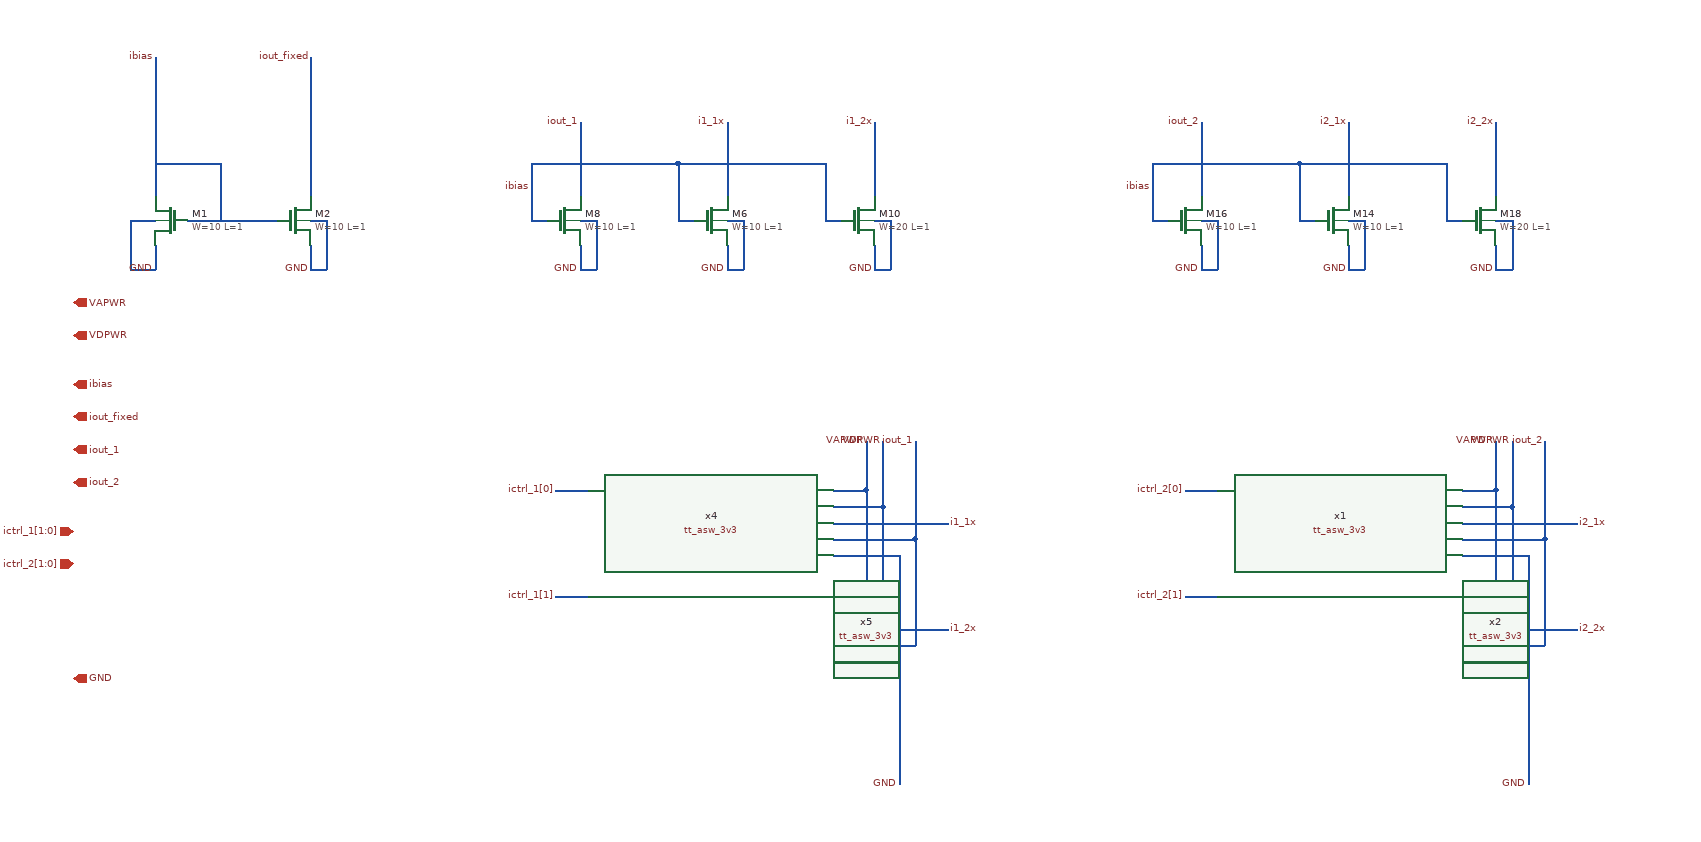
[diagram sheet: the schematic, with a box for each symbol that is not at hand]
v {xschem version=3.1.0 file_version=1.2
}
G {}
K {}
V {}
S {}
E {}
N 0 130 0 160 {
lab=GND}
N 80 30 80 100 {
lab=ibias}
N 190 130 190 160 {
lab=GND}
N 190 100 210 100 {
lab=GND}
N 210 100 210 160 {
lab=GND}
N -30 100 0 100 {
lab=GND}
N -30 100 -30 160 {
lab=GND}
N 190 -20 190 70 {
lab=iout_fixed}
N 0 30 80 30 {
lab=ibias}
N 0 -100 0 70 {
lab=ibias}
N 190 -100 190 -20 {
lab=iout_fixed}
N 830 600 970 600 {
lab=i1_2x}
N 460 30 460 100 {
lab=ibias}
N 700 -20 700 70 {
lab=i1_1x}
N 640 30 640 100 {
lab=ibias}
N 640 100 660 100 {
lab=ibias}
N 460 30 640 30 {
lab=ibias}
N 520 -20 520 70 {
lab=iout_1}
N 460 100 480 100 {
lab=ibias}
N 640 30 820 30 {
lab=ibias}
N 880 -20 880 70 {
lab=i1_2x}
N 820 30 820 100 {
lab=ibias}
N 820 100 840 100 {
lab=ibias}
N 490 430 530 430 {
lab=ictrl_1[0]}
N 490 560 530 560 {
lab=ictrl_1[1]}
N 830 430 870 430 {
lab=VAPWR}
N 830 560 870 560 {
lab=VAPWR}
N 830 450 890 450 {
lab=VDPWR}
N 830 580 890 580 {
lab=VDPWR}
N 830 510 910 510 {
lab=GND}
N 910 510 910 790 {
lab=GND}
N 830 640 910 640 {
lab=GND}
N 870 370 870 430 {
lab=VAPWR}
N 890 370 890 450 {
lab=VDPWR}
N 830 490 930 490 {
lab=iout_1}
N 830 620 930 620 {
lab=iout_1}
N 930 370 930 490 {
lab=iout_1}
N 830 470 970 470 {
lab=i1_1x}
N 830 600 970 600 {
lab=i1_2x}
N 1220 30 1220 100 {
lab=ibias}
N 1460 -20 1460 70 {
lab=i2_1x}
N 1400 30 1400 100 {
lab=ibias}
N 1400 100 1420 100 {
lab=ibias}
N 1220 30 1400 30 {
lab=ibias}
N 1280 -20 1280 70 {
lab=iout_2}
N 1220 100 1240 100 {
lab=ibias}
N 1400 30 1580 30 {
lab=ibias}
N 1640 -20 1640 70 {
lab=i2_2x}
N 1580 30 1580 100 {
lab=ibias}
N 1580 100 1600 100 {
lab=ibias}
N 1460 130 1460 160 {
lab=GND}
N 1480 100 1480 160 {
lab=GND}
N 1460 100 1480 100 {
lab=GND}
N 520 100 540 100 {
lab=GND}
N 540 100 540 160 {
lab=GND}
N 520 130 520 160 {
lab=GND}
N 700 100 720 100 {
lab=GND}
N 720 100 720 160 {
lab=GND}
N 700 130 700 160 {
lab=GND}
N 880 100 900 100 {
lab=GND}
N 900 100 900 160 {
lab=GND}
N 880 130 880 160 {
lab=GND}
N 1280 100 1300 100 {
lab=GND}
N 1300 100 1300 160 {
lab=GND}
N 1280 130 1280 160 {
lab=GND}
N 1640 100 1660 100 {
lab=GND}
N 1660 100 1660 160 {
lab=GND}
N 1640 130 1640 160 {
lab=GND}
N 1600 600 1740 600 {
lab=i2_2x}
N 1260 430 1300 430 {
lab=ictrl_2[0]}
N 1260 560 1300 560 {
lab=ictrl_2[1]}
N 1600 430 1640 430 {
lab=VAPWR}
N 1600 560 1640 560 {
lab=VAPWR}
N 1600 450 1660 450 {
lab=VDPWR}
N 1600 580 1660 580 {
lab=VDPWR}
N 1600 510 1680 510 {
lab=GND}
N 1680 510 1680 790 {
lab=GND}
N 1600 640 1680 640 {
lab=GND}
N 1640 370 1640 430 {
lab=VAPWR}
N 1660 370 1660 450 {
lab=VDPWR}
N 1600 490 1700 490 {
lab=iout_2}
N 1600 620 1700 620 {
lab=iout_2}
N 1700 370 1700 490 {
lab=iout_2}
N 1600 470 1740 470 {
lab=i2_1x}
N 1600 600 1740 600 {
lab=i2_2x}
N 40 100 150 100 {
lab=ibias}
N 1280 160 1300 160 {
lab=GND}
N 1460 160 1480 160 {
lab=GND}
N 1640 160 1660 160 {
lab=GND}
N 190 160 210 160 {
lab=GND}
N -30 160 -0 160 {
lab=GND}
N 520 160 540 160 {
lab=GND}
N 700 160 720 160 {
lab=GND}
N 880 160 900 160 {
lab=GND}
N 870 430 870 560 {
lab=VAPWR}
N 890 450 890 580 {
lab=VDPWR}
N 930 490 930 620 {
lab=iout_1}
N 1640 430 1640 560 {
lab=VAPWR}
N 1660 450 1660 580 {
lab=VDPWR}
N 1700 490 1700 620 {
lab=iout_2}
C {sky130_fd_pr/nfet_g5v0d10v5.sym} 20 100 0 1 {name=M1
L=1
W=10
nf=2
mult=1
ad="'int((nf+1)/2) * W/nf * 0.29'" 
pd="'2*int((nf+1)/2) * (W/nf + 0.29)'"
as="'int((nf+2)/2) * W/nf * 0.29'" 
ps="'2*int((nf+2)/2) * (W/nf + 0.29)'"
nrd="'0.29 / W'" nrs="'0.29 / W'"
sa=0 sb=0 sd=0
model=nfet_g5v0d10v5
spiceprefix=X
}
C {sky130_fd_pr/nfet_g5v0d10v5.sym} 170 100 0 0 {name=M2
L=1
W=10
nf=2
mult=1
ad="'int((nf+1)/2) * W/nf * 0.29'" 
pd="'2*int((nf+1)/2) * (W/nf + 0.29)'"
as="'int((nf+2)/2) * W/nf * 0.29'" 
ps="'2*int((nf+2)/2) * (W/nf + 0.29)'"
nrd="'0.29 / W'" nrs="'0.29 / W'"
sa=0 sb=0 sd=0
model=nfet_g5v0d10v5
spiceprefix=X
}
C {devices/iopin.sym} -100 300 0 1 {name=p8 lab=ibias}
C {devices/iopin.sym} -100 340 0 1 {name=p3 lab=iout_fixed}
C {devices/iopin.sym} -100 380 0 1 {name=p6 lab=iout_1}
C {devices/ipin.sym} -100 480 0 0 {name=p4 lab=ictrl_1[1:0]}
C {devices/ipin.sym} -100 520 0 0 {name=p5 lab=ictrl_2[1:0]}
C {devices/iopin.sym} -100 420 0 1 {name=p7 lab=iout_2}
C {devices/iopin.sym} -100 200 0 1 {name=p9 lab=VAPWR}
C {devices/iopin.sym} -100 240 0 1 {name=p10 lab=VDPWR}
C {sky130_fd_pr/nfet_g5v0d10v5.sym} 680 100 0 0 {name=M6
L=1
W=10
nf=2
mult=1
ad="'int((nf+1)/2) * W/nf * 0.29'" 
pd="'2*int((nf+1)/2) * (W/nf + 0.29)'"
as="'int((nf+2)/2) * W/nf * 0.29'" 
ps="'2*int((nf+2)/2) * (W/nf + 0.29)'"
nrd="'0.29 / W'" nrs="'0.29 / W'"
sa=0 sb=0 sd=0
model=nfet_g5v0d10v5
spiceprefix=X
}
C {sky130_fd_pr/nfet_g5v0d10v5.sym} 500 100 0 0 {name=M8
L=1
W=10
nf=2
mult=1
ad="'int((nf+1)/2) * W/nf * 0.29'" 
pd="'2*int((nf+1)/2) * (W/nf + 0.29)'"
as="'int((nf+2)/2) * W/nf * 0.29'" 
ps="'2*int((nf+2)/2) * (W/nf + 0.29)'"
nrd="'0.29 / W'" nrs="'0.29 / W'"
sa=0 sb=0 sd=0
model=nfet_g5v0d10v5
spiceprefix=X
}
C {sky130_fd_pr/nfet_g5v0d10v5.sym} 860 100 0 0 {name=M10
L=1
W=20
nf=4
mult=1
ad="'int((nf+1)/2) * W/nf * 0.29'" 
pd="'2*int((nf+1)/2) * (W/nf + 0.29)'"
as="'int((nf+2)/2) * W/nf * 0.29'" 
ps="'2*int((nf+2)/2) * (W/nf + 0.29)'"
nrd="'0.29 / W'" nrs="'0.29 / W'"
sa=0 sb=0 sd=0
model=nfet_g5v0d10v5
spiceprefix=X
}
C {devices/lab_pin.sym} 520 -20 3 1 {name=p2 sig_type=std_logic lab=iout_1}
C {devices/lab_pin.sym} 700 -20 3 1 {name=p21 sig_type=std_logic lab=i1_1x}
C {devices/lab_pin.sym} 880 -20 3 1 {name=p22 sig_type=std_logic lab=i1_2x}
C {devices/lab_pin.sym} 190 -100 3 1 {name=p23 sig_type=std_logic lab=iout_fixed}
C {devices/lab_pin.sym} 0 -100 3 1 {name=p24 sig_type=std_logic lab=ibias}
C {tt_asw_3v3.sym} 680 470 0 0 {name=x4}
C {tt_asw_3v3.sym} 680 600 0 0 {name=x5}
C {devices/lab_pin.sym} 490 430 0 0 {name=p25 sig_type=std_logic lab=ictrl_1[0]}
C {devices/lab_pin.sym} 490 560 0 0 {name=p26 sig_type=std_logic lab=ictrl_1[1]}
C {devices/lab_pin.sym} 870 370 1 0 {name=p28 sig_type=std_logic lab=VAPWR}
C {devices/lab_pin.sym} 890 370 1 0 {name=p29 sig_type=std_logic lab=VDPWR}
C {devices/lab_pin.sym} 930 370 1 0 {name=p30 sig_type=std_logic lab=iout_1}
C {devices/lab_pin.sym} 970 470 0 1 {name=p31 sig_type=std_logic lab=i1_1x}
C {devices/lab_pin.sym} 970 600 0 1 {name=p32 sig_type=std_logic lab=i1_2x}
C {sky130_fd_pr/nfet_g5v0d10v5.sym} 1440 100 0 0 {name=M14
L=1
W=10
nf=2
mult=1
ad="'int((nf+1)/2) * W/nf * 0.29'" 
pd="'2*int((nf+1)/2) * (W/nf + 0.29)'"
as="'int((nf+2)/2) * W/nf * 0.29'" 
ps="'2*int((nf+2)/2) * (W/nf + 0.29)'"
nrd="'0.29 / W'" nrs="'0.29 / W'"
sa=0 sb=0 sd=0
model=nfet_g5v0d10v5
spiceprefix=X
}
C {sky130_fd_pr/nfet_g5v0d10v5.sym} 1260 100 0 0 {name=M16
L=1
W=10
nf=2
mult=1
ad="'int((nf+1)/2) * W/nf * 0.29'" 
pd="'2*int((nf+1)/2) * (W/nf + 0.29)'"
as="'int((nf+2)/2) * W/nf * 0.29'" 
ps="'2*int((nf+2)/2) * (W/nf + 0.29)'"
nrd="'0.29 / W'" nrs="'0.29 / W'"
sa=0 sb=0 sd=0
model=nfet_g5v0d10v5
spiceprefix=X
}
C {sky130_fd_pr/nfet_g5v0d10v5.sym} 1620 100 0 0 {name=M18
L=1
W=20
nf=4
mult=1
ad="'int((nf+1)/2) * W/nf * 0.29'" 
pd="'2*int((nf+1)/2) * (W/nf + 0.29)'"
as="'int((nf+2)/2) * W/nf * 0.29'" 
ps="'2*int((nf+2)/2) * (W/nf + 0.29)'"
nrd="'0.29 / W'" nrs="'0.29 / W'"
sa=0 sb=0 sd=0
model=nfet_g5v0d10v5
spiceprefix=X
}
C {devices/lab_pin.sym} 1280 -20 3 1 {name=p35 sig_type=std_logic lab=iout_2}
C {devices/lab_pin.sym} 1460 -20 3 1 {name=p36 sig_type=std_logic lab=i2_1x}
C {devices/lab_pin.sym} 1640 -20 3 1 {name=p37 sig_type=std_logic lab=i2_2x}
C {devices/lab_pin.sym} 460 60 0 0 {name=p38 sig_type=std_logic lab=ibias}
C {devices/lab_pin.sym} 1220 60 0 0 {name=p39 sig_type=std_logic lab=ibias}
C {tt_asw_3v3.sym} 1450 470 0 0 {name=x1}
C {tt_asw_3v3.sym} 1450 600 0 0 {name=x2}
C {devices/lab_pin.sym} 1260 430 0 0 {name=p1 sig_type=std_logic lab=ictrl_2[0]}
C {devices/lab_pin.sym} 1260 560 0 0 {name=p11 sig_type=std_logic lab=ictrl_2[1]}
C {devices/lab_pin.sym} 1640 370 1 0 {name=p13 sig_type=std_logic lab=VAPWR}
C {devices/lab_pin.sym} 1660 370 1 0 {name=p14 sig_type=std_logic lab=VDPWR}
C {devices/lab_pin.sym} 1700 370 1 0 {name=p15 sig_type=std_logic lab=iout_2}
C {devices/lab_pin.sym} 1740 470 0 1 {name=p16 sig_type=std_logic lab=i2_1x}
C {devices/lab_pin.sym} 1740 600 0 1 {name=p17 sig_type=std_logic lab=i2_2x}
C {devices/lab_pin.sym} 910 790 3 0 {name=p19 sig_type=std_logic lab=GND}
C {devices/lab_pin.sym} 1680 790 3 0 {name=p20 sig_type=std_logic lab=GND}
C {devices/lab_pin.sym} 0 160 3 0 {name=p34 sig_type=std_logic lab=GND}
C {devices/lab_pin.sym} 190 160 3 0 {name=p40 sig_type=std_logic lab=GND}
C {devices/lab_pin.sym} 520 160 3 0 {name=p41 sig_type=std_logic lab=GND}
C {devices/lab_pin.sym} 700 160 3 0 {name=p42 sig_type=std_logic lab=GND}
C {devices/lab_pin.sym} 880 160 3 0 {name=p43 sig_type=std_logic lab=GND}
C {devices/lab_pin.sym} 1280 160 3 0 {name=p44 sig_type=std_logic lab=GND}
C {devices/lab_pin.sym} 1460 160 3 0 {name=p45 sig_type=std_logic lab=GND}
C {devices/lab_pin.sym} 1640 160 3 0 {name=p46 sig_type=std_logic lab=GND}
C {devices/iopin.sym} -100 660 0 1 {name=p47 lab=GND}
